VERSION 5.7 ;
  NOWIREEXTENSIONATPIN ON ;
  DIVIDERCHAR "/" ;
  BUSBITCHARS "[]" ;
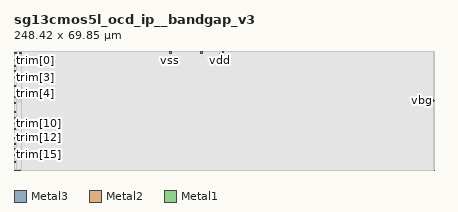
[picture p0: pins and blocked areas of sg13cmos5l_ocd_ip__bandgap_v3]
MACRO sg13cmos5l_ocd_ip__bandgap_v3
  CLASS BLOCK ;
  FOREIGN sg13cmos5l_ocd_ip__bandgap_v3 ;
  ORIGIN 51.785 133.215 ;
  SIZE 248.420 BY 69.850 ;
  PIN vdd
    ANTENNAGATEAREA 35.000000 ;
    ANTENNADIFFAREA 452.990784 ;
    PORT
      LAYER Metal3 ;
        RECT 69.605 -64.560 70.605 -64.460 ;
    END
  END vdd
  PIN vbg
    ANTENNAGATEAREA 48.000000 ;
    ANTENNADIFFAREA 10.880000 ;
    PORT
      LAYER Metal3 ;
        RECT 195.485 -92.690 196.485 -91.690 ;
    END
  END vbg
  PIN vss
    ANTENNAGATEAREA 76.658401 ;
    ANTENNADIFFAREA 568.622009 ;
    PORT
      LAYER Metal3 ;
        RECT 40.130 -64.420 41.130 -63.420 ;
    END
  END vss
  PIN ibias1_250n
    ANTENNADIFFAREA 2.720000 ;
    PORT
      LAYER Metal3 ;
        RECT 58.770 -64.375 59.775 -63.375 ;
    END
  END ibias1_250n
  PIN trim[15]
    ANTENNAGATEAREA 4.483600 ;
    ANTENNADIFFAREA 2.015400 ;
    PORT
      LAYER Metal2 ;
        RECT -51.765 -124.580 -50.765 -124.075 ;
    END
  END trim[15]
  PIN trim[14]
    ANTENNAGATEAREA 4.483600 ;
    ANTENNADIFFAREA 2.015400 ;
    PORT
      LAYER Metal2 ;
        RECT -51.765 -121.205 -50.765 -120.680 ;
    END
  END trim[14]
  PIN trim[13]
    ANTENNAGATEAREA 4.483600 ;
    ANTENNADIFFAREA 2.015400 ;
    PORT
      LAYER Metal2 ;
        RECT -51.785 -117.850 -50.785 -117.325 ;
    END
  END trim[13]
  PIN trim[12]
    ANTENNAGATEAREA 4.483600 ;
    ANTENNADIFFAREA 2.015400 ;
    PORT
      LAYER Metal2 ;
        RECT -51.785 -114.480 -50.785 -113.955 ;
    END
  END trim[12]
  PIN trim[11]
    ANTENNAGATEAREA 4.483600 ;
    ANTENNADIFFAREA 2.015400 ;
    PORT
      LAYER Metal2 ;
        RECT -51.785 -109.215 -50.785 -108.690 ;
    END
  END trim[11]
  PIN trim[10]
    ANTENNAGATEAREA 4.483600 ;
    ANTENNADIFFAREA 2.015400 ;
    PORT
      LAYER Metal2 ;
        RECT -51.775 -105.850 -50.775 -105.325 ;
    END
  END trim[10]
  PIN trim[9]
    ANTENNAGATEAREA 4.483600 ;
    ANTENNADIFFAREA 2.015400 ;
    PORT
      LAYER Metal2 ;
        RECT -51.750 -102.505 -50.750 -101.980 ;
    END
  END trim[9]
  PIN trim[8]
    ANTENNAGATEAREA 4.483600 ;
    ANTENNADIFFAREA 2.015400 ;
    PORT
      LAYER Metal2 ;
        RECT -51.760 -99.105 -50.760 -98.580 ;
    END
  END trim[8]
  PIN trim[7]
    ANTENNAGATEAREA 4.483600 ;
    ANTENNADIFFAREA 2.015400 ;
    PORT
      LAYER Metal2 ;
        RECT -51.765 -93.845 -50.765 -93.320 ;
    END
  END trim[7]
  PIN trim[6]
    ANTENNAGATEAREA 4.483600 ;
    ANTENNADIFFAREA 2.015400 ;
    PORT
      LAYER Metal2 ;
        RECT -51.750 -90.495 -50.750 -89.970 ;
    END
  END trim[6]
  PIN trim[5]
    ANTENNAGATEAREA 4.483600 ;
    ANTENNADIFFAREA 2.015400 ;
    PORT
      LAYER Metal2 ;
        RECT -51.775 -87.110 -50.775 -86.585 ;
    END
  END trim[5]
  PIN trim[4]
    ANTENNAGATEAREA 4.483600 ;
    ANTENNADIFFAREA 2.015400 ;
    PORT
      LAYER Metal2 ;
        RECT -51.785 -83.745 -50.785 -83.220 ;
    END
  END trim[4]
  PIN trim[3]
    ANTENNAGATEAREA 4.483600 ;
    ANTENNADIFFAREA 2.015400 ;
    PORT
      LAYER Metal2 ;
        RECT -51.765 -78.490 -50.765 -77.965 ;
    END
  END trim[3]
  PIN trim[2]
    ANTENNAGATEAREA 4.483600 ;
    ANTENNADIFFAREA 2.015400 ;
    PORT
      LAYER Metal2 ;
        RECT -51.740 -75.120 -50.740 -74.595 ;
    END
  END trim[2]
  PIN trim[1]
    ANTENNAGATEAREA 4.483600 ;
    ANTENNADIFFAREA 2.015400 ;
    PORT
      LAYER Metal2 ;
        RECT -51.760 -71.755 -50.760 -71.230 ;
    END
  END trim[1]
  PIN trim[0]
    ANTENNAGATEAREA 4.483600 ;
    ANTENNADIFFAREA 2.015400 ;
    PORT
      LAYER Metal2 ;
        RECT -51.730 -68.410 -50.730 -67.885 ;
    END
  END trim[0]
  PIN dvss
    ANTENNAGATEAREA 5.000000 ;
    ANTENNADIFFAREA 29.998400 ;
    PORT
      LAYER Metal1 ;
        RECT -48.535 -64.435 -47.535 -63.435 ;
    END
  END dvss
  PIN dvdd
    ANTENNAGATEAREA 2.100000 ;
    ANTENNADIFFAREA 36.458401 ;
    PORT
      LAYER Metal1 ;
        RECT -51.590 -64.490 -50.590 -63.490 ;
    END
  END dvdd
  PIN ena
    ANTENNAGATEAREA 4.483600 ;
    ANTENNADIFFAREA 2.015400 ;
    PORT
      LAYER Metal2 ;
        RECT -51.780 -128.490 -50.780 -127.980 ;
    END
  END ena
  PIN ibias2_1u
    ANTENNADIFFAREA 1.360000 ;
    PORT
      LAYER Metal3 ;
        RECT 71.260 -64.005 72.260 -63.385 ;
    END
  END ibias2_1u
  OBS
      LAYER GatPoly ;
        RECT -51.520 -130.810 159.720 -64.030 ;
      LAYER Metal1 ;
        RECT -50.410 -64.615 -48.715 -63.380 ;
        RECT -47.355 -64.615 196.500 -63.380 ;
        RECT -50.410 -64.670 196.500 -64.615 ;
        RECT -51.590 -131.025 196.500 -64.670 ;
      LAYER Metal2 ;
        RECT -51.735 -67.675 196.420 -63.380 ;
        RECT -50.520 -68.620 196.420 -67.675 ;
        RECT -51.735 -71.020 196.420 -68.620 ;
        RECT -50.550 -71.965 196.420 -71.020 ;
        RECT -51.735 -74.385 196.420 -71.965 ;
        RECT -50.530 -75.330 196.420 -74.385 ;
        RECT -51.735 -77.755 196.420 -75.330 ;
        RECT -50.555 -78.700 196.420 -77.755 ;
        RECT -51.735 -83.010 196.420 -78.700 ;
        RECT -50.575 -83.955 196.420 -83.010 ;
        RECT -51.735 -86.375 196.420 -83.955 ;
        RECT -50.565 -87.320 196.420 -86.375 ;
        RECT -51.735 -89.760 196.420 -87.320 ;
        RECT -50.540 -90.705 196.420 -89.760 ;
        RECT -51.735 -93.110 196.420 -90.705 ;
        RECT -50.555 -94.055 196.420 -93.110 ;
        RECT -51.735 -98.370 196.420 -94.055 ;
        RECT -50.550 -99.315 196.420 -98.370 ;
        RECT -51.735 -101.770 196.420 -99.315 ;
        RECT -50.540 -102.715 196.420 -101.770 ;
        RECT -51.735 -105.115 196.420 -102.715 ;
        RECT -50.565 -106.060 196.420 -105.115 ;
        RECT -51.735 -108.480 196.420 -106.060 ;
        RECT -50.575 -109.425 196.420 -108.480 ;
        RECT -51.735 -113.745 196.420 -109.425 ;
        RECT -50.575 -114.690 196.420 -113.745 ;
        RECT -51.735 -117.115 196.420 -114.690 ;
        RECT -50.575 -118.060 196.420 -117.115 ;
        RECT -51.735 -120.470 196.420 -118.060 ;
        RECT -50.555 -121.415 196.420 -120.470 ;
        RECT -51.735 -123.865 196.420 -121.415 ;
        RECT -50.555 -124.790 196.420 -123.865 ;
        RECT -51.735 -127.770 196.420 -124.790 ;
        RECT -50.570 -128.700 196.420 -127.770 ;
        RECT -51.735 -132.665 196.420 -128.700 ;
      LAYER Metal3 ;
        RECT -50.115 -64.630 39.920 -63.365 ;
        RECT 41.340 -64.585 58.560 -63.365 ;
        RECT 59.985 -64.215 71.050 -63.365 ;
        RECT 72.470 -64.215 196.635 -63.365 ;
        RECT 59.985 -64.250 196.635 -64.215 ;
        RECT 59.985 -64.585 69.395 -64.250 ;
        RECT 41.340 -64.630 69.395 -64.585 ;
        RECT -50.115 -64.770 69.395 -64.630 ;
        RECT 70.815 -64.770 196.635 -64.250 ;
        RECT -50.115 -91.480 196.635 -64.770 ;
        RECT -50.115 -92.900 195.275 -91.480 ;
        RECT -50.115 -132.930 196.635 -92.900 ;
      LAYER Metal4 ;
        RECT -47.185 -133.215 196.305 -63.395 ;
  END
END sg13cmos5l_ocd_ip__bandgap_v3
END LIBRARY

